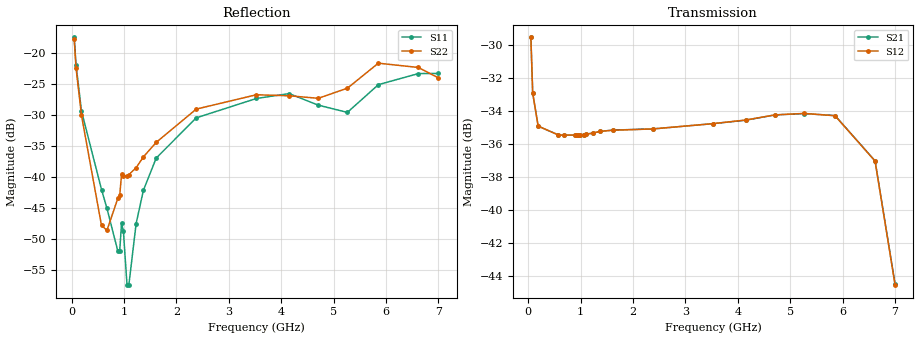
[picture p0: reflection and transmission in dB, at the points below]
! Integrated Device Technology
! Corporate Headquarters
! 6024 Silver Creek Valley Road
! San Jose, CA 95138  USA
! Phone:  1-408-284-8200
! Toll Free:  1-800-223-1366
! Webpage:  http://www.idt.com/
! Timing and RF Division
! 515 Groton Road, Suite 102
! Westford, MA 01886-6024
! Device:  F2258
! Description: Voltage Variable RF Attenuator
! Frequency:  50.0 -  6000.00 MHz
! Package:  3x3 mm Thin QFN Plastic Package: 16 pin
! Ports:  2 RF, 2 DC
!  Pin  1  = NC
!  Pin  2  = NC
!  Pin  3  = RF2  = Port 2
!  Pin  4  = GND
!  Pin  5  = Vdd
!  Pin  6  = NC
!  Pin  7  = VCTRL
!  Pin  8  = NC
!  Pin  9  = GND
!  Pin 10  = RF1  = Port 1
!  Pin 11  = NC
!  Pin 12  = NC
!  Pin 13  = NC
!  Pin 14  = NC
!  Pin 15  = NC
!  Pin 16  = NC
! Vcntrl:  2.300 Volts
! Vdd:  +3.300 Volts
! Current:  1.150 mA
! Data:  The device was measured on a the F2258 evaluation board which has
!  individual transmission lines to the RF pins.  Data was collected
!  using a calibrated network analyzer.  The evaluation board was
!  de-embedded using a TRL calibration technique.
!  The reference plane is the edge of the package pin.
! Misc:  SN 10
!  Action Tracker AT0285
! Date Measured:  2014-12-10
! Date:  2016-01-13  MJV
! Note:
!  Integrated Device Technology supplies this data as a sample of measured
!  data at the package pin for this product.  Your particular data for this
!  product may vary.
!  Data was taken at 25 degrees C.
!  Integrated Device Technology reserves the right to change this data at anytime.
!Freq_(GHz)  S11M_(dB)  S11P_(deg)  S21M_(dB)  S21P_(deg)  S12M_(dB)  S12P_(deg)  S22M_(dB)  S22P_(deg)
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# GHz S dB R 50
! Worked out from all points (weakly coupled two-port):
!   201 points, 50 MHz to 7 GHz, reference 50 ohm
!   highest |S21| = -29.52 dB at 50 MHz (marker M1); lowest = -44.5 dB at 7 GHz (marker M2)
!   lowest |S11| = -57.5 dB at 1.058 GHz (marker M3), VSWR 1.00, Z = 49.9 + j0.0567 ohm
!   |S11| at or under -10 dB: start of sweep to end of sweep
!   |S22| runs from -48.9 to -17.8 dB; largest |S21 - S12| = 7e-05
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0.05  -17.56 -111.0  -29.52 -68.5  -29.52 -68.5  -17.83 -111.4
0.08475  -21.98 -107.5  -32.89 -48.8  -32.89 -48.8  -22.49 -107.7
0.189  -29.43 -109.5  -34.90 -24.8  -34.90 -24.8  -30.12 -110.3
0.57125  -42.09 -124.7  -35.43 -10.3  -35.43 -10.3  -47.88 -165.7
0.6755  -45.14 -131.8  -35.45 -9.4  -35.45 -9.4  -48.66 147.7
0.884  -52.06 166.6  -35.45 -8.4  -35.44 -8.4  -43.45 120.0
0.91875  -51.97 150.6  -35.44 -8.3  -35.44 -8.3  -43.02 117.6
0.9535  -47.51 -162.9  -35.45 -8.2  -35.45 -8.2  -39.63 123.3
0.98825  -48.74 -174.9  -35.43 -8.1  -35.43 -8.1  -39.93 121.1
1.05775  -57.49 154.8  -35.41 -7.9  -35.41 -8.0  -39.88 106.7
1.0925  -57.48 120.0  -35.40 -7.9  -35.40 -7.9  -39.69 102.8
1.2315  -47.57 47.1  -35.32 -7.9  -35.32 -7.9  -38.57 81.0
1.3705  -42.20 37.0  -35.22 -8.3  -35.22 -8.3  -36.82 68.1
1.61375  -37.02 32.8  -35.14 -9.6  -35.15 -9.6  -34.49 54.3
2.37825  -30.53 48.2  -35.07 -13.2  -35.07 -13.2  -29.12 43.9
3.525  -27.41 91.7  -34.75 -19.6  -34.75 -19.6  -26.81 67.8
4.1505  -26.62 105.0  -34.54 -24.0  -34.53 -24.0  -26.97 75.4
4.7065  -28.48 95.6  -34.22 -28.7  -34.22 -28.7  -27.38 59.0
5.2625  -29.65 54.4  -34.14 -34.9  -34.13 -34.8  -25.75 21.7
5.85325  -25.18 29.8  -34.26 -45.4  -34.27 -45.5  -21.72 -2.2
6.61775  -23.39 49.7  -37.01 -68.6  -37.02 -68.6  -22.41 -44.1
7  -23.38 84.5  -44.49 -61.6  -44.54 -61.1  -24.10 -130.0
